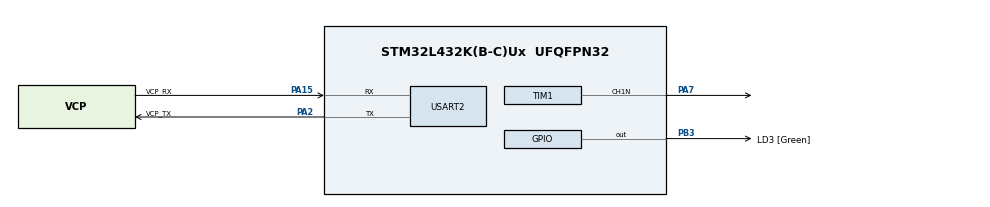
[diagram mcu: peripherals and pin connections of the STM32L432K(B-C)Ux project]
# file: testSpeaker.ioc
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Mcu.Family=STM32L4
Mcu.Name=STM32L432K(B-C)Ux
Mcu.Package=UFQFPN32
NVIC.PriorityGroup=NVIC_PRIORITYGROUP_4
PA0.GPIO_Label=MCO [High speed clock in]
PA0.Mode=HSE-External-Clock-Source-for-LittleOrca
PA0.Signal=RCC_CK_IN
PA13\ (JTMS-SWDIO).GPIO_Label=SWDIO
PA13\ (JTMS-SWDIO).Mode=Serial_Wire
PA13\ (JTMS-SWDIO).Signal=SYS_JTMS-SWDIO
PA14\ (JTCK-SWCLK).GPIO_Label=SWCLK
PA14\ (JTCK-SWCLK).Mode=Serial_Wire
PA14\ (JTCK-SWCLK).Signal=SYS_JTCK-SWCLK
PA15\ (JTDI).GPIO_Label=VCP_RX
PA15\ (JTDI).Mode=Asynchronous
PA15\ (JTDI).Signal=USART2_RX
PA2.GPIO_Label=VCP_TX
PA2.Mode=Asynchronous
PA2.Signal=USART2_TX
PA7.Mode=PWM Generation1 CH1N
PA7.Signal=TIM1_CH1N
PB3\ (JTDO-TRACESWO).GPIO_Label=LD3 [Green]
PB3\ (JTDO-TRACESWO).Signal=GPIO_Output
PC14-OSC32_IN\ (PC14).Mode=LSE-External-Oscillator
PC14-OSC32_IN\ (PC14).Signal=RCC_OSC32_IN
PC15-OSC32_OUT\ (PC15).Mode=LSE-External-Oscillator
PC15-OSC32_OUT\ (PC15).Signal=RCC_OSC32_OUT
ProjectManager.HeapSize=0x200
ProjectManager.StackSize=0x400
ProjectManager.TargetToolchain=STM32CubeIDE
RCC.AHBFreq_Value=32000000
RCC.APB1Freq_Value=32000000
RCC.APB1TimFreq_Value=32000000
RCC.APB2CLKDivider=RCC_HCLK_DIV2
RCC.APB2Freq_Value=16000000
RCC.APB2TimFreq_Value=32000000
RCC.CortexFreq_Value=32000000
RCC.HCLKFreq_Value=32000000
RCC.HSE_VALUE=8000000
RCC.HSI16_VALUE=16000000
RCC.HSI48_VALUE=48000000
RCC.HSI_VALUE=16000000
RCC.MSI_VALUE=4000000
RCC.PLLMUL=RCC_PLLMUL_4
RCC.PLLN=16
RCC.SYSCLKFreq_VALUE=32000000
RCC.SYSCLKSource=RCC_SYSCLKSOURCE_PLLCLK
RCC.VCOOutputFreq_Value=64000000
TIM1.Channel-PWM\ Generation1\ CH1N=TIM_CHANNEL_1
USART2.VirtualMode-Asynchronous=VM_ASYNC
VP_TIM1_VS_ClockSourceINT.Mode=Internal
board=NUCLEO-L432KC

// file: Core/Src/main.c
/* USER CODE BEGIN Header */
/**
  ******************************************************************************
  * @file           : main.c
  * @brief          : Main program body
  ******************************************************************************
  * @attention
  *
  * Copyright (c) 2023 STMicroelectronics.
  * All rights reserved.
  *
  * This software is licensed under terms that can be found in the LICENSE file
  * in the root directory of this software component.
  * If no LICENSE file comes with this software, it is provided AS-IS.
  *
  ******************************************************************************
  */
/* USER CODE END Header */
#include "main.h"

TIM_HandleTypeDef htim1;

UART_HandleTypeDef huart2;

void SystemClock_Config(void);
static void MX_GPIO_Init(void);
static void MX_USART2_UART_Init(void);
static void MX_TIM1_Init(void);

int main(void)
{

  /* MCU Configuration--------------------------------------------------------*/

  /* Reset of all peripherals, Initializes the Flash interface and the Systick. */
  HAL_Init();

  /* Configure the system clock */
  SystemClock_Config();

  /* Initialize all configured peripherals */
  MX_GPIO_Init();
  MX_USART2_UART_Init();
  MX_TIM1_Init();
  /* USER CODE BEGIN 2 */
  HAL_TIMEx_PWMN_Start(&htim1, TIM_CHANNEL_1);
  /* USER CODE END 2 */

  /* Infinite loop */
  while (1)
  {

  }
}

void SystemClock_Config(void)
{
  RCC_OscInitTypeDef RCC_OscInitStruct = {0};
  RCC_ClkInitTypeDef RCC_ClkInitStruct = {0};

  /** Configure the main internal regulator output voltage
  */
  if (HAL_PWREx_ControlVoltageScaling(PWR_REGULATOR_VOLTAGE_SCALE1) != HAL_OK)
  {
    Error_Handler();
  }

  /** Configure LSE Drive Capability
  */
  HAL_PWR_EnableBkUpAccess();
  __HAL_RCC_LSEDRIVE_CONFIG(RCC_LSEDRIVE_LOW);

  /** Initializes the RCC Oscillators according to the specified parameters
  * in the RCC_OscInitTypeDef structure.
  */
  RCC_OscInitStruct.OscillatorType = RCC_OSCILLATORTYPE_LSE|RCC_OSCILLATORTYPE_MSI;
  RCC_OscInitStruct.LSEState = RCC_LSE_ON;
  RCC_OscInitStruct.MSIState = RCC_MSI_ON;
  RCC_OscInitStruct.MSICalibrationValue = 0;
  RCC_OscInitStruct.MSIClockRange = RCC_MSIRANGE_6;
  RCC_OscInitStruct.PLL.PLLState = RCC_PLL_ON;
  RCC_OscInitStruct.PLL.PLLSource = RCC_PLLSOURCE_MSI;
  RCC_OscInitStruct.PLL.PLLM = 1;
  RCC_OscInitStruct.PLL.PLLN = 16;
  RCC_OscInitStruct.PLL.PLLP = RCC_PLLP_DIV7;
  RCC_OscInitStruct.PLL.PLLQ = RCC_PLLQ_DIV2;
  RCC_OscInitStruct.PLL.PLLR = RCC_PLLR_DIV2;
  if (HAL_RCC_OscConfig(&RCC_OscInitStruct) != HAL_OK)
  {
    Error_Handler();
  }

  /** Initializes the CPU, AHB and APB buses clocks
  */
  RCC_ClkInitStruct.ClockType = RCC_CLOCKTYPE_HCLK|RCC_CLOCKTYPE_SYSCLK
                              |RCC_CLOCKTYPE_PCLK1|RCC_CLOCKTYPE_PCLK2;
  RCC_ClkInitStruct.SYSCLKSource = RCC_SYSCLKSOURCE_PLLCLK;
  RCC_ClkInitStruct.AHBCLKDivider = RCC_SYSCLK_DIV1;
  RCC_ClkInitStruct.APB1CLKDivider = RCC_HCLK_DIV1;
  RCC_ClkInitStruct.APB2CLKDivider = RCC_HCLK_DIV1;

  if (HAL_RCC_ClockConfig(&RCC_ClkInitStruct, FLASH_LATENCY_1) != HAL_OK)
  {
    Error_Handler();
  }

  /** Enable MSI Auto calibration
  */
  HAL_RCCEx_EnableMSIPLLMode();
}

static void MX_TIM1_Init(void)
{

  TIM_ClockConfigTypeDef sClockSourceConfig = {0};
  TIM_MasterConfigTypeDef sMasterConfig = {0};
  TIM_OC_InitTypeDef sConfigOC = {0};
  TIM_BreakDeadTimeConfigTypeDef sBreakDeadTimeConfig = {0};

  htim1.Instance = TIM1;
  htim1.Init.Prescaler = 1000;
  htim1.Init.CounterMode = TIM_COUNTERMODE_UP;
  htim1.Init.Period = 32000;   // Period value should not be greater than 0xFFFF
  htim1.Init.ClockDivision = TIM_CLOCKDIVISION_DIV1;
  htim1.Init.RepetitionCounter = 0;
  htim1.Init.AutoReloadPreload = TIM_AUTORELOAD_PRELOAD_DISABLE;
  if (HAL_TIM_Base_Init(&htim1) != HAL_OK)
  {
    Error_Handler();
  }
  sClockSourceConfig.ClockSource = TIM_CLOCKSOURCE_INTERNAL;
  if (HAL_TIM_ConfigClockSource(&htim1, &sClockSourceConfig) != HAL_OK)
  {
    Error_Handler();
  }
  if (HAL_TIM_PWM_Init(&htim1) != HAL_OK)
  {
    Error_Handler();
  }
  sMasterConfig.MasterOutputTrigger = TIM_TRGO_RESET;
  sMasterConfig.MasterOutputTrigger2 = TIM_TRGO2_RESET;
  sMasterConfig.MasterSlaveMode = TIM_MASTERSLAVEMODE_DISABLE;
  if (HAL_TIMEx_MasterConfigSynchronization(&htim1, &sMasterConfig) != HAL_OK)
  {
    Error_Handler();
  }
  sConfigOC.OCMode = TIM_OCMODE_PWM1;
  sConfigOC.Pulse = 16000;  // 50% ON time
  sConfigOC.OCPolarity = TIM_OCPOLARITY_HIGH;
  sConfigOC.OCNPolarity = TIM_OCNPOLARITY_HIGH;
  sConfigOC.OCFastMode = TIM_OCFAST_DISABLE;
  sConfigOC.OCIdleState = TIM_OCIDLESTATE_RESET;
  sConfigOC.OCNIdleState = TIM_OCNIDLESTATE_RESET;
  if (HAL_TIM_PWM_ConfigChannel(&htim1, &sConfigOC, TIM_CHANNEL_1) != HAL_OK)
  {
    Error_Handler();
  }
  sBreakDeadTimeConfig.OffStateRunMode = TIM_OSSR_DISABLE;
  sBreakDeadTimeConfig.OffStateIDLEMode = TIM_OSSI_DISABLE;
  sBreakDeadTimeConfig.LockLevel = TIM_LOCKLEVEL_OFF;
  sBreakDeadTimeConfig.DeadTime = 0;
  sBreakDeadTimeConfig.BreakState = TIM_BREAK_DISABLE;
  sBreakDeadTimeConfig.BreakPolarity = TIM_BREAKPOLARITY_HIGH;
  sBreakDeadTimeConfig.BreakFilter = 0;
  sBreakDeadTimeConfig.Break2State = TIM_BREAK2_DISABLE;
  sBreakDeadTimeConfig.Break2Polarity = TIM_BREAK2POLARITY_HIGH;
  sBreakDeadTimeConfig.Break2Filter = 0;
  sBreakDeadTimeConfig.AutomaticOutput = TIM_AUTOMATICOUTPUT_DISABLE;
  if (HAL_TIMEx_ConfigBreakDeadTime(&htim1, &sBreakDeadTimeConfig) != HAL_OK)
  {
    Error_Handler();
  }
  HAL_TIM_MspPostInit(&htim1);

}

static void MX_USART2_UART_Init(void)
{

  huart2.Instance = USART2;
  huart2.Init.BaudRate = 115200;
  huart2.Init.WordLength = UART_WORDLENGTH_8B;
  huart2.Init.StopBits = UART_STOPBITS_1;
  huart2.Init.Parity = UART_PARITY_NONE;
  huart2.Init.Mode = UART_MODE_TX_RX;
  huart2.Init.HwFlowCtl = UART_HWCONTROL_NONE;
  huart2.Init.OverSampling = UART_OVERSAMPLING_16;
  huart2.Init.OneBitSampling = UART_ONE_BIT_SAMPLE_DISABLE;
  huart2.AdvancedInit.AdvFeatureInit = UART_ADVFEATURE_NO_INIT;
  if (HAL_UART_Init(&huart2) != HAL_OK)
  {
    Error_Handler();
  }

}

static void MX_GPIO_Init(void)
{
  GPIO_InitTypeDef GPIO_InitStruct = {0};

  /* GPIO Ports Clock Enable */
  __HAL_RCC_GPIOC_CLK_ENABLE();
  __HAL_RCC_GPIOA_CLK_ENABLE();
  __HAL_RCC_GPIOB_CLK_ENABLE();

  /*Configure GPIO pin Output Level */
  HAL_GPIO_WritePin(LD3_GPIO_Port, LD3_Pin, GPIO_PIN_RESET);

  /*Configure GPIO pin : LD3_Pin */
  GPIO_InitStruct.Pin = LD3_Pin;
  GPIO_InitStruct.Mode = GPIO_MODE_OUTPUT_PP;
  GPIO_InitStruct.Pull = GPIO_NOPULL;
  GPIO_InitStruct.Speed = GPIO_SPEED_FREQ_LOW;
  HAL_GPIO_Init(LD3_GPIO_Port, &GPIO_InitStruct);

}

void Error_Handler(void)
{
  __disable_irq();
  while (1)
  {
  }
}
